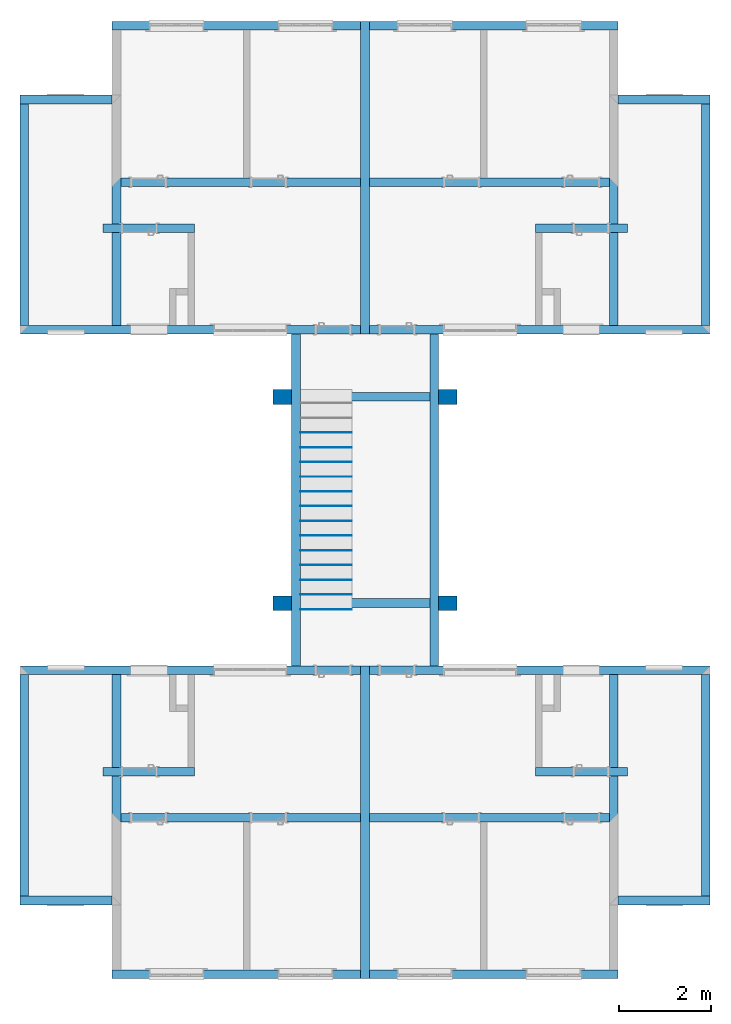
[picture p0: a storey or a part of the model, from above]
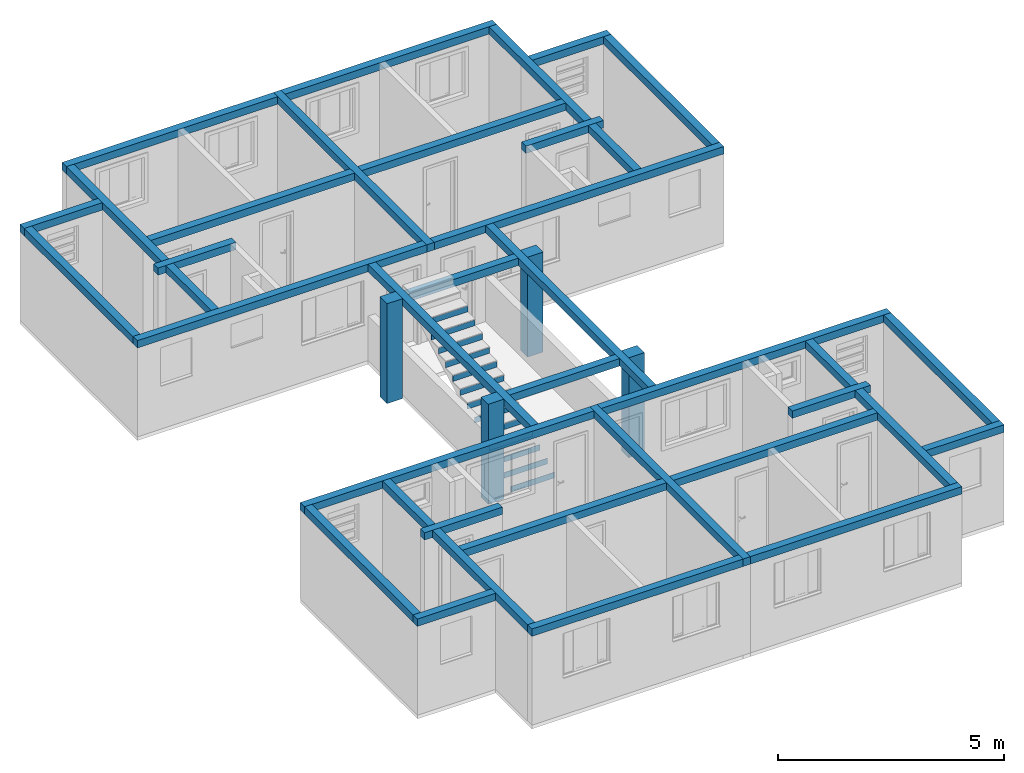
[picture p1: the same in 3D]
Properties of the parts of a building model (IFC2X3)

# File
Description: ViewDefinition [CoordinationView_V2.0, QuantityTakeOffAddOnView], Option [Elements to export: All elements on Current Story], Option [Partial Structure Display: Entire Model], Option [IFC Domain: All], Option [Structural Function: All Elements], Option [Convert Grid elements: On], Option [Convert IFC Annotations and Archicad 2D elements: Off], Option [Convert 2D symbols of Doors and Windows: Off], Option [Export geometries that Participates in Collision Detection only: Off], Option [Split complex elements: Off], Option [Material Preservation: Explode where necessary], Option [Elements in Solid Element Operations: Extruded/revolved], Option [Elements with junctions: Extruded/revolved without junctions], Option [IFC Model position: Survey Point and Project Origin], Option [Curtain Wall export mode: Container Element], Option [Railing export mode: Single Element], Option [Stair export mode: Container Element], Option [Properties To Export: All properties], Option [Space containment: Off], Option [Geometry to type objects: Off], Option [Element Properties: Visible Only], Option [Building Material Properties: Off], Option [Element Parameters: Off], Option [Component Parameters: All], Option [IFC Base Quantities: On], Option [Door Window Parameters: On], Option [IFC Space boundaries: Off], Option [Archicad Zone Categories as IFC Space classification data: Off], Option [Element Classifications: On]
File name: C:\Users\jplen\Downloads\Modelagem - Pavimento tipo V052H-01.ifc
Time: 2024-05-23T11:47:46
Author: Architect
Organization: Building Designer Office
Written by: DDS_IFC v3.0
Made in: IFC file generated by Graphisoft Archicad 27.0.0 BRA FULL Windows version (IFC add-on version: 3001 BRA FULL).
Authorization: The authorising person

# IfcSite, Local
RefLatitude: -23, -32, 0, 0; RefLongitude: -46, -38, 0, 0; RefElevation: 0 mm
BaseQuantities - GrossPerimeter: 0 mm; GrossArea: 0 m2

# IfcBuilding, Construção
BaseQuantities - GrossFloorArea: 217.987 m2

# IfcBuildingStorey, Pavimento Tipo
In: Construção
Elevation: 0 mm
BaseQuantities - NetHeight: 2600 mm; GrossHeight: 2600 mm; Height: 2600 mm; GrossFloorArea: 217.987 m2

# IfcSpace: Circulação (2)
In: Pavimento Tipo
Type - ElementType: EXTERNAL; PredefinedType: USERDEFINED
InteriorOrExteriorSpace: INTERNAL
AC_Pset_RenovationAndPhasing - Renovation Status: Existing
Pset_SpaceCommon - Category: Circulação
BaseQuantities - Height: 2600 mm; FinishCeilingHeight: 2600 mm; FinishFloorHeight: 0 mm; ClearHeight: 2600 mm
Name | LongName | Classification | GrossFloorArea (m2) = NetFloorArea (m2) = SpaceNetFloorAreaBOMA (m2) = SpaceUsableFloorAreaBOMA (m2) = GrossCeilingArea (m2) = NetCeilingArea (m2) | GrossWallArea (m2) | NetWallArea (m2) | GrossPerimeter (mm) = NetPerimeter (mm) | GrossVolume (m3) = NetVolume (m3)
10 | Circulação Horizontal Externa | Espaço Externo (Classificação Archicad); 4A 16 04 04 Saguão (NBR 15965-6 4A) | 14.8841 | 25.032 | 18.312 | 22280 | 38.6987
09 | Caixa de escada | Espaço Externo (Classificação Archicad); 4A 16 01 04 Escada (NBR 15965-6 4A) | 5.376 | 5.76 | 5.76 | 11840 | 13.9776

# IfcSpace: Circulação (4)
In: Pavimento Tipo
Type - ElementType: INTERNAL; PredefinedType: USERDEFINED
LongName: Circulação; InteriorOrExteriorSpace: INTERNAL; Classification: Espaço Residencial (Classificação Archicad); 4A 19 04 10 Circulação (NBR 15965-6 4A)
Pset_SpaceCommon - Category: Circulação
AC_Pset_RenovationAndPhasing - Renovation Status: Existing
BaseQuantities - Height: 2600 mm; FinishCeilingHeight: 2600 mm; FinishFloorHeight: 0 mm; ClearHeight: 2600 mm; GrossFloorArea: 1.4499 m2; NetFloorArea: 1.4499 m2; SpaceNetFloorAreaBOMA: 1.4499 m2; SpaceUsableFloorAreaBOMA: 1.4499 m2; GrossCeilingArea: 1.4499 m2; NetCeilingArea: 1.4499 m2; GrossWallArea: 8.592 m2; NetWallArea: 5.232 m2; GrossPerimeter: 5200 mm; NetPerimeter: 5200 mm; GrossVolume: 3.76974 m3; NetVolume: 3.76974 m3
Name
Apartamento 1 - 06
Apartamento 2 - 06
Apartamento 3 - 06
Apartamento 4 - 06

# IfcSpace: Área privativa (20)
In: Pavimento Tipo
Type - ElementType: INTERNAL; PredefinedType: USERDEFINED
InteriorOrExteriorSpace: INTERNAL
AC_Pset_RenovationAndPhasing - Renovation Status: Existing
BaseQuantities - Height: 2600 mm; FinishCeilingHeight: 2600 mm; FinishFloorHeight: 0 mm; ClearHeight: 2600 mm
Pset_SpaceCommon - Category: Área privativa
Name | LongName | Classification | GrossFloorArea (m2) = NetFloorArea (m2) = SpaceNetFloorAreaBOMA (m2) = SpaceUsableFloorAreaBOMA (m2) = GrossCeilingArea (m2) = NetCeilingArea (m2) | GrossWallArea (m2) | NetWallArea (m2) | GrossPerimeter (mm) = NetPerimeter (mm) | GrossVolume (m3) = NetVolume (m3)
Apartamento 1 - 07 | Cozinha | 4A 19 01 25 Cozinha (NBR 15965-6 4A); Espaço Residencial (Classificação Archicad) | 8.6681 | 30.792 | 29.192 | 13640 | 22.5371
Apartamento 1 - 01 | Quarto 01 | Espaço Residencial (Classificação Archicad); 4A 19 01 01 Dormitório (NBR 15965-6 4A) | 7.7361 | 27.618 | 24.498 | 11240 | 20.1139
Apartamento 1 - 04 | Sala de estar | Espaço Residencial (Classificação Archicad); 4A 19 01 07 Sala de Estar (NBR 15965-6 4A) | 10.8661 | 30.234 | 24.954 | 13240 | 28.2519
Apartamento 1 - 03 | Banheiro | Espaço Residencial (Classificação Archicad); 4A 19 04 07 Banheiro residencial (NBR 15965-6 4A) | 2.6146 | 17.138 | 14.978 | 6940 | 6.79796
Apartamento 1 - 02 | Quarto 02 | Espaço Residencial (Classificação Archicad); 4A 19 01 01 Dormitório (NBR 15965-6 4A) | 8.5386 | 28.818 | 25.698 | 11740 | 22.2004
Apartamento 2 - 07 | Cozinha | 4A 19 01 25 Cozinha (NBR 15965-6 4A); Espaço Residencial (Classificação Archicad) | 8.6681 | 30.792 | 29.192 | 13640 | 22.5371
Apartamento 2 - 01 | Quarto 01 | Espaço Residencial (Classificação Archicad); 4A 19 01 01 Dormitório (NBR 15965-6 4A) | 7.7361 | 27.618 | 24.498 | 11240 | 20.1139
Apartamento 2 - 03 | Banheiro | Espaço Residencial (Classificação Archicad); 4A 19 04 07 Banheiro residencial (NBR 15965-6 4A) | 2.6146 | 17.138 | 14.978 | 6940 | 6.79796
Apartamento 2 - 04 | Sala de estar | Espaço Residencial (Classificação Archicad); 4A 19 01 07 Sala de Estar (NBR 15965-6 4A) | 10.8661 | 30.234 | 24.954 | 13240 | 28.2519
Apartamento 2 - 02 | Quarto 02 | Espaço Residencial (Classificação Archicad); 4A 19 01 01 Dormitório (NBR 15965-6 4A) | 8.5386 | 28.818 | 25.698 | 11740 | 22.2004
Apartamento 3 - 07 | Cozinha | 4A 19 01 25 Cozinha (NBR 15965-6 4A); Espaço Residencial (Classificação Archicad) | 8.6681 | 30.792 | 29.192 | 13640 | 22.5371
Apartamento 3 - 01 | Quarto 01 | Espaço Residencial (Classificação Archicad); 4A 19 01 01 Dormitório (NBR 15965-6 4A) | 7.7361 | 27.618 | 24.498 | 11240 | 20.1139
Apartamento 3 - 04 | Sala de estar | Espaço Residencial (Classificação Archicad); 4A 19 01 07 Sala de Estar (NBR 15965-6 4A) | 10.8661 | 30.234 | 24.954 | 13240 | 28.2519
Apartamento 3 - 03 | Banheiro | Espaço Residencial (Classificação Archicad); 4A 19 04 07 Banheiro residencial (NBR 15965-6 4A) | 2.6146 | 17.138 | 14.978 | 6940 | 6.79796
Apartamento 3 - 02 | Quarto 02 | Espaço Residencial (Classificação Archicad); 4A 19 01 01 Dormitório (NBR 15965-6 4A) | 8.5386 | 28.818 | 25.698 | 11740 | 22.2004
Apartamento 4 - 07 | Cozinha | 4A 19 01 25 Cozinha (NBR 15965-6 4A); Espaço Residencial (Classificação Archicad) | 8.6681 | 30.792 | 29.192 | 13640 | 22.5371
Apartamento 4 - 01 | Quarto 01 | Espaço Residencial (Classificação Archicad); 4A 19 01 01 Dormitório (NBR 15965-6 4A) | 7.7361 | 27.618 | 24.498 | 11240 | 20.1139
Apartamento 4 - 03 | Banheiro | Espaço Residencial (Classificação Archicad); 4A 19 04 07 Banheiro residencial (NBR 15965-6 4A) | 2.6146 | 17.138 | 14.978 | 6940 | 6.79796
Apartamento 4 - 04 | Sala de estar | Espaço Residencial (Classificação Archicad); 4A 19 01 07 Sala de Estar (NBR 15965-6 4A) | 10.8661 | 30.234 | 24.954 | 13240 | 28.2519
Apartamento 4 - 02 | Quarto 02 | Espaço Residencial (Classificação Archicad); 4A 19 01 01 Dormitório (NBR 15965-6 4A) | 8.5386 | 28.818 | 25.698 | 11740 | 22.2004

# IfcSpace: Área técnica (4)
In: Pavimento Tipo
Type - ElementType: INTERNAL; PredefinedType: USERDEFINED
LongName: Shaft do banheiro; InteriorOrExteriorSpace: INTERNAL; Classification: Espaço Residencial (Classificação Archicad); 4A 13 01 13 22 Shaft de Distribuição de Hidráulica (NBR 15965-6 4A)
AC_Pset_RenovationAndPhasing - Renovation Status: Existing
Pset_SpaceCommon - Category: Área técnica
BaseQuantities - Height: 2600 mm; FinishCeilingHeight: 2600 mm; FinishFloorHeight: 0 mm; ClearHeight: 2600 mm; GrossFloorArea: 0.1716 m2; NetFloorArea: 0.1716 m2; SpaceNetFloorAreaBOMA: 0.1716 m2; SpaceUsableFloorAreaBOMA: 0.1716 m2; GrossCeilingArea: 0.1716 m2; NetCeilingArea: 0.1716 m2; GrossWallArea: 4.732 m2; NetWallArea: 4.732 m2; GrossPerimeter: 1840 mm; NetPerimeter: 1840 mm; GrossVolume: 0.44616 m3; NetVolume: 0.44616 m3
Name
Apartamento 1 - 05
Apartamento 2 - 05
Apartamento 3 - 05
Apartamento 4 - 05

# IfcBeam: Concreto - Estrutural 190 x 200 (38)
In: Pavimento Tipo
Type - PredefinedType: BEAM
Classification: 3E 12 06 02 00 Viga (NBR 15965-5 3E); Viga (Classificação Archicad); Material: Concreto - Estrutural
AC_Pset_RenovationAndPhasing - Renovation Status: Existing
Pset_ManufacturerTypeInformation - ProductionYear: DD/MM/YYYY
Pset_BeamCommon - LoadBearing: yes; Reference: Concreto - Estrutural 190 x 200
Component Properties - Concreto - Estrutural, Tipo de Componente: Núcleo
BaseQuantities - Width: 190 mm; Depth: 200 mm; CrossSectionArea: 0.038 m2
Component Quantities - Concreto - Estrutural, Espessura do Componente: 190 mm; Concreto - Estrutural, Altura do Componente Retangular: 200 mm; Concreto - Estrutural, Largura do Componente Retangular: 190 mm; Concreto - Estrutural, Área de Seção Transversal do Componente: 0.038 m2
Name | Description | IsExternal | Concreto - Estrutural, Carbono Incorporado | Concreto - Estrutural, Energia Incorporada (MJ) | NetSurfaceAreaExtrudedSides (m2) = OuterSurfaceArea (m2) | Length (mm) | TotalSurfaceArea (m2) = GrossSurfaceArea (m2) = NetSurfaceArea (m2) | GrossVolume (m3) | NetVolume (m3) = Concreto - Estrutural, Volume Componente (Líquido) (m3) = Concreto - Estrutural, Volume do componente (Bruto) (m3) = Concreto - Estrutural, Volume Componente (Condicional) (m3) | Concreto - Estrutural, Massa (kg) | Concreto - Estrutural, Área de Componente Projetada (Líquida) (m2) = Concreto - Estrutural, Área de Componente Projetada (Bruta) (m2)
Apartamento 1 - V06 | Viga-externa-inloco-concreto_armado-19cm x 20cm | yes | 83.238 (kgCO₂) | 807.156 | 3.7518 | 4810 | 3.8278 | 0.19 | 0.18278 | 420.394 | 0.962
Apartamento 1 - V07 | Viga-interna-inloco-concreto_armado-19cm x 20cm | no | 90.1601 (kgCO₂) | 874.28 | 4.0638 | 5210 | 4.1398 | 0.2052 | 0.19798 | 455.354 | 1.042
Apartamento 1 - V05 | Viga-externa-inloco-concreto_armado-19cm x 20cm | yes | 34.6104 (kgCO₂) | 335.616 | 1.56 | 2000 | 1.636 | 0.076 | 0.076 | 174.8 | 0.4
Apartamento 1 - V04 | Viga-externa-inloco-concreto_armado-19cm x 20cm | yes | 128.058 (kgCO₂) | 1241.78 | 5.772 | 7400 | 5.848 | 0.2812 | 0.2812 | 646.76 | 1.48
Apartamento 1 - V03 | Viga-interna-inloco-concreto_armado-19cm x 20cm | no | 34.4373 (kgCO₂) | 333.938 | 1.5522 | 1990 | 1.6282 | 0.07562 | 0.07562 | 173.926 | 0.398
Apartamento 1 - V01 | Viga-externa-inloco-concreto_armado-19cm x 20cm | yes | 93.4481 (kgCO₂) | 906.163 | 4.212 | 5400 | 4.288 | 0.2052 | 0.2052 | 471.96 | 1.08
Apartamento 1 - V02 | Viga-externa-inloco-concreto_armado-19cm x 20cm | yes | 72.8549 (kgCO₂) | 706.472 | 3.2838 | 4210 | 3.3598 | 0.1672 | 0.15998 | 367.954 | 0.842
Apartamento 1 - V09 | Viga-interna-inloco-concreto_armado-19cm x 20cm | no | 34.7835 (kgCO₂) | 337.294 | 1.5678 | 2010 | 1.6438 | 0.0836 | 0.07638 | 175.674 | 0.402
Apartamentos 1 e 2 - V08 | Viga-interna-inloco-concreto_armado-19cm x 20cm | no | 115.858 (kgCO₂) | 1123.47 | 5.2221 | 6790 | 5.2981 | 0.25441 | 0.25441 | 585.143 | 1.358
Apartamento 2 - V06 | Viga-externa-inloco-concreto_armado-19cm x 20cm | yes | 83.238 (kgCO₂) | 807.156 | 3.7518 | 4810 | 3.8278 | 0.19 | 0.18278 | 420.394 | 0.962
Apartamento 2 - V07 | Viga-interna-inloco-concreto_armado-19cm x 20cm | no | 90.1601 (kgCO₂) | 874.28 | 4.0638 | 5210 | 4.1398 | 0.21242 | 0.19798 | 455.354 | 1.042
Apartamento 2 - V05 | Viga-externa-inloco-concreto_armado-19cm x 20cm | yes | 34.6104 (kgCO₂) | 335.616 | 1.56 | 2000 | 1.636 | 0.076 | 0.076 | 174.8 | 0.4
Apartamento 2 - V04 | Viga-externa-inloco-concreto_armado-19cm x 20cm | yes | 129.702 (kgCO₂) | 1257.72 | 5.8461 | 7590 | 5.9221 | 0.28481 | 0.28481 | 655.063 | 1.518
Apartamento 2 - V02 | Viga-externa-inloco-concreto_armado-19cm x 20cm | yes | 72.8549 (kgCO₂) | 706.472 | 3.2838 | 4210 | 3.3598 | 0.1672 | 0.15998 | 367.954 | 0.842
Apartamento 2 - V03 | Viga-interna-inloco-concreto_armado-19cm x 20cm | no | 34.4373 (kgCO₂) | 333.938 | 1.5522 | 1990 | 1.6282 | 0.07562 | 0.07562 | 173.926 | 0.398
Apartamento 2 - V09 | Viga-interna-inloco-concreto_armado-19cm x 20cm | no | 34.7835 (kgCO₂) | 337.294 | 1.5678 | 2010 | 1.6438 | 0.0836 | 0.07638 | 175.674 | 0.402
Apartamento 2 - V01 | Viga-externa-inloco-concreto_armado-19cm x 20cm | yes | 93.4481 (kgCO₂) | 906.163 | 4.212 | 5400 | 4.288 | 0.21242 | 0.2052 | 471.96 | 1.08
Apartamento 3 - V06 | Viga-externa-inloco-concreto_armado-19cm x 20cm | yes | 83.238 (kgCO₂) | 807.156 | 3.7518 | 4810 | 3.8278 | 0.19 | 0.18278 | 420.394 | 0.962
Apartamento 3 - V07 | Viga-interna-inloco-concreto_armado-19cm x 20cm | no | 90.1601 (kgCO₂) | 874.28 | 4.0638 | 5210 | 4.1398 | 0.2052 | 0.19798 | 455.354 | 1.042
Apartamento 3 - V05 | Viga-externa-inloco-concreto_armado-19cm x 20cm | yes | 34.6104 (kgCO₂) | 335.616 | 1.56 | 2000 | 1.636 | 0.076 | 0.076 | 174.8 | 0.4
Apartamento 3 - V04 | Viga-externa-inloco-concreto_armado-19cm x 20cm | yes | 128.058 (kgCO₂) | 1241.78 | 5.772 | 7400 | 5.848 | 0.2812 | 0.2812 | 646.76 | 1.48
Apartamento 3 - V03 | Viga-interna-inloco-concreto_armado-19cm x 20cm | no | 34.4373 (kgCO₂) | 333.938 | 1.5522 | 1990 | 1.6282 | 0.07562 | 0.07562 | 173.926 | 0.398
Apartamento 3 - V02 | Viga-externa-inloco-concreto_armado-19cm x 20cm | yes | 72.8549 (kgCO₂) | 706.472 | 3.2838 | 4210 | 3.3598 | 0.1672 | 0.15998 | 367.954 | 0.842
Apartamento 3 - V01 | Viga-externa-inloco-concreto_armado-19cm x 20cm | yes | 93.4481 (kgCO₂) | 906.163 | 4.212 | 5400 | 4.288 | 0.2052 | 0.2052 | 471.96 | 1.08
Apartamento 3 - V09 | Viga-interna-inloco-concreto_armado-19cm x 20cm | no | 34.7835 (kgCO₂) | 337.294 | 1.5678 | 2010 | 1.6438 | 0.0836 | 0.07638 | 175.674 | 0.402
Apartamentos 3 e 4 - V08 | Viga-interna-inloco-concreto_armado-19cm x 20cm | no | 115.858 (kgCO₂) | 1123.47 | 5.2221 | 6790 | 5.2981 | 0.25441 | 0.25441 | 585.143 | 1.358
Apartamento 4 - V06 | Viga-externa-inloco-concreto_armado-19cm x 20cm | yes | 83.238 (kgCO₂) | 807.156 | 3.7518 | 4810 | 3.8278 | 0.19 | 0.18278 | 420.394 | 0.962
Apartamento 4 - V07 | Viga-interna-inloco-concreto_armado-19cm x 20cm | no | 90.1601 (kgCO₂) | 874.28 | 4.0638 | 5210 | 4.1398 | 0.21242 | 0.19798 | 455.354 | 1.042
Apartamento 4 - V05 | Viga-externa-inloco-concreto_armado-19cm x 20cm | yes | 34.6104 (kgCO₂) | 335.616 | 1.56 | 2000 | 1.636 | 0.076 | 0.076 | 174.8 | 0.4
Apartamento 4 - V04 | Viga-externa-inloco-concreto_armado-19cm x 20cm | yes | 129.702 (kgCO₂) | 1257.72 | 5.8461 | 7590 | 5.9221 | 0.28481 | 0.28481 | 655.063 | 1.518
Apartamento 4 - V02 | Viga-externa-inloco-concreto_armado-19cm x 20cm | yes | 72.8549 (kgCO₂) | 706.472 | 3.2838 | 4210 | 3.3598 | 0.1672 | 0.15998 | 367.954 | 0.842
Apartamento 4 - V01 | Viga-externa-inloco-concreto_armado-19cm x 20cm | yes | 93.4481 (kgCO₂) | 906.163 | 4.212 | 5400 | 4.288 | 0.21242 | 0.2052 | 471.96 | 1.08
Apartamento 4 - V09 | Viga-interna-inloco-concreto_armado-19cm x 20cm | no | 34.7835 (kgCO₂) | 337.294 | 1.5678 | 2010 | 1.6438 | 0.0836 | 0.07638 | 175.674 | 0.402
Apartamento 4 - V03 | Viga-interna-inloco-concreto_armado-19cm x 20cm | no | 34.4373 (kgCO₂) | 333.938 | 1.5522 | 1990 | 1.6282 | 0.07562 | 0.07562 | 173.926 | 0.398
2 x Núcleo - V03 | Viga-externa-inloco-concreto_armado-19cm x 20cm |  | 124.77 (kgCO₂) | 1209.9 | 5.6238 | 7210 | 5.6998 | 0.28842 | 0.27398 | 630.154 | 1.442
2 x Núcleo - V03 | Viga-externa-inloco-concreto_armado-19cm x 20cm |  | 48.6276 (kgCO₂) | 471.54 | 2.1918 | 2810 | 2.2678 | 0.114 | 0.10678 | 245.594 | 0.562

# IfcColumn: Concreto Armado - Estrutural 400 x 320 (4)
In: Pavimento Tipo
Type - PredefinedType: COLUMN
Classification: Pilar (Classificação Archicad); 3E 12 10 02 02 Pilar (NBR 15965-5 3E); Material: Concreto Armado - Estrutural
Pset_ManufacturerTypeInformation - ProductionYear: DD/MM/YYYY
AC_Pset_RenovationAndPhasing - Renovation Status: Existing
BaseQuantities - Width: 400 mm; Depth: 320 mm; CrossSectionArea: 0.128 m2
Pset_ColumnCommon - LoadBearing: yes; Reference: Concreto Armado - Estrutural 400 x 320
Component Quantities - Concreto Armado - Estrutural, Espessura do Componente: 400 mm; Concreto Armado - Estrutural, Altura do Componente Retangular: 320 mm; Concreto Armado - Estrutural, Largura do Componente Retangular: 400 mm; Concreto Armado - Estrutural, Área de Seção Transversal do Componente: 0.128 m2
Component Properties - Concreto Armado - Estrutural, Tipo de Componente: Núcleo
Name | Length (mm) | OuterSurfaceArea (m2) | TotalSurfaceArea (m2) = GrossSurfaceArea (m2) | GrossVolume (m3) = NetVolume (m3) = Concreto Armado - Estrutural, Volume Componente (Líquido) (m3) = Concreto Armado - Estrutural, Volume do componente (Bruto) (m3) | Concreto Armado - Estrutural, Massa (kg) | Concreto Armado - Estrutural, Carbono Incorporado | Concreto Armado - Estrutural, Energia Incorporada (MJ)
Núcleo - P02 | 2700 | 3.888 | 4.144 | 0.3456 | 829.44 | 200.724 (kgCO₂) | 1932.6
Núcleo - P01 | 2700 | 3.888 | 4.144 | 0.3456 | 829.44 | 200.724 (kgCO₂) | 1932.6
Núcleo - P03 | 2702.18 | 3.89114 | 4.14714 | 0.345879 | 830.11 | 200.887 (kgCO₂) | 1934.16
Núcleo - P04 | 2702.18 | 3.89114 | 4.14714 | 0.345879 | 830.11 | 200.887 (kgCO₂) | 1934.16

# IfcDoor: Porta 27 (8)
In: Pavimento Tipo
Type - OperationType: SINGLE_SWING_LEFT; ParameterTakesPrecedence: no; Sizeable: no
Type - Door Lining Properties - LiningThickness: 50 mm; CasingThickness: 70 mm; CasingDepth: 19 mm
Type - Door Panel Properties - Panel 1 - PanelDepth: 30 mm; PanelOperation: SWINGING; PanelWidth: 1; PanelPosition: MIDDLE
OverallHeight: 2100 mm; OverallWidth: 800 mm; Classification: 3E 20 02 02 04 Porta de girar (NBR 15965-5 3E); Porta (Classificação Archicad)
Pset_DoorCommon - ThermalTransmittance: 0; IsExternal: no
AC_Pset_RenovationAndPhasing - Renovation Status: Existing
BaseQuantities - Height: 2100 mm; Width: 800 mm; Perimeter: 5800 mm; Area: 1.68 m2; Volume: 0.10295 m3; Depth: 190 mm; NetVolume: 0.10295 m3
Component Quantities - Component, Volume Componente (Líquido): 0.10295 m3; Component, Volume do componente (Bruto): 0.10295 m3
Name | Description
Apartamento 1 - P01 | Porta-interna-genérico-madeira-girar- 80cm x 210cm
Apartamento 1 - P02 | Porta-interna-genérico-madeira-girar-80cm x 210cm
Apartamento 2 - P03 | Porta-interna-genérico-madeira-girar-80cm x 210cm
Apartamento 2 - P04 | Porta-interna-genérico-madeira-girar-80cm x 210cm
Apartamento 3 - P01 | Porta-interna-genérico-madeira-girar- 80cm x 210cm
Apartamento 3 - P02 | Porta-interna-genérico-madeira-girar-80cm x 210cm
Apartamento 4 - P04 | Porta-interna-genérico-madeira-girar-80cm x 210cm
Apartamento 4 - P03 | Porta-interna-genérico-madeira-girar-80cm x 210cm

# IfcDoor: Porta 27 (8)
In: Pavimento Tipo
Type - OperationType: SINGLE_SWING_RIGHT; ParameterTakesPrecedence: no; Sizeable: no
Type - Door Lining Properties - LiningThickness: 50 mm; CasingThickness: 70 mm; CasingDepth: 19 mm
Type - Door Panel Properties - Panel 1 - PanelDepth: 30 mm; PanelOperation: SWINGING; PanelWidth: 1; PanelPosition: MIDDLE
OverallHeight: 2100 mm; OverallWidth: 800 mm; Classification: 3E 20 02 02 04 Porta de girar (NBR 15965-5 3E); Porta (Classificação Archicad)
Pset_DoorCommon - ThermalTransmittance: 0; IsExternal: no
AC_Pset_RenovationAndPhasing - Renovation Status: Existing
Component Quantities - Component, Volume Componente (Líquido): 0.10295 m3; Component, Volume do componente (Bruto): 0.10295 m3
BaseQuantities - Height: 2100 mm; Width: 800 mm; Perimeter: 5800 mm; Area: 1.68 m2; Volume: 0.10295 m3; Depth: 190 mm; NetVolume: 0.10295 m3
Name | Description
Apartamento 4 - P02 | Porta-interna-genérico-madeira-girar-80cm x 210cm
Apartamento 1 - P04 | Porta-interna-genérico-madeira-girar-80cm x 210cm
Apartamento 1 - P03 | Porta-interna-genérico-madeira-girar-80cm x 210cm
Apartamento 2 - P01 | Porta-interna-genérico-madeira-girar- 80cm x 210cm
Apartamento 2 - P02 | Porta-interna-genérico-madeira-girar-80cm x 210cm
Apartamento 3 - P03 | Porta-interna-genérico-madeira-girar-80cm x 210cm
Apartamento 3 - P04 | Porta-interna-genérico-madeira-girar-80cm x 210cm
Apartamento 4 - P01 | Porta-interna-genérico-madeira-girar- 80cm x 210cm

# IfcMember: IfcMember (15)
In: Pavimento Tipo
Type - ElementType: Stair Riser; PredefinedType: USERDEFINED
Classification: Espelho de Escada (Classificação Archicad); Material: Madeira
AC_Pset_RenovationAndPhasing - Renovation Status: Existing
Component Properties - Madeira, Carbono Incorporado: 0.270816 (kgCO₂); Madeira, Energia Incorporada: 6.19752 MJ
BaseQuantities - GrossVolume: 0.001736 m3; NetVolume: 0.001736 m3
Component Quantities - Madeira, Massa: 0.5208 kg; Madeira, Volume Componente (Líquido): 0.001736 m3; Madeira, Volume do componente (Bruto): 0.001736 m3

# IfcMember: IfcMember (15)
In: Pavimento Tipo
Type - ElementType: Stair Tread; PredefinedType: USERDEFINED
Classification: Piso de Escada (Classificação Archicad); Material: Madeira
AC_Pset_RenovationAndPhasing - Renovation Status: Existing
Name | GrossVolume (m3) = NetVolume (m3) = Madeira, Volume Componente (Líquido) (m3) = Madeira, Volume do componente (Bruto) (m3) | Madeira, Massa (kg) | Madeira, Carbono Incorporado | Madeira, Energia Incorporada (MJ)
14 x Núcleo - Piso Esc. - 017 | 0.00956207 | 2.86862 | 1.49168 (kgCO₂) | 34.1366
Núcleo - Piso Esc. - 017 | 0.00886207 | 2.65862 | 1.38248 (kgCO₂) | 31.6376

# IfcOpeningElement (40)
In: Pavimento Tipo
BaseQuantities - Depth: 190 mm
Name | Height (mm) | Width (mm) | Area (m2) | Volume (m3)
Apartamento 4 - P02 | 2100 | 800 | 1.68 | 0.10295
Apartamento 1 - J04 | 1000 | 800 | 0.8 | 0.0194095
Apartamento 1 - J06 | 1200 | 1200 | 1.44 | 0.049487
Apartamento 1 - J05 | 1200 | 1200 | 1.44 | 0.049487
Apartamento 1 - J01 | 1200 | 1600 | 1.92 | 0.0569999
Apartamento 1 - J02 | 600 | 800 | 0.48 | 0.0253701
Apartamento 1 - J03 | 1000 | 800 | 0.8 | 0.0194095
Apartamento 1 - P01 | 2100 | 800 | 1.68 | 0.10295
Apartamento 1 - P03 | 2100 | 800 | 1.68 | 0.10295
Apartamento 1 - P04 | 2100 | 800 | 1.68 | 0.10295
Apartamento 2 - J04 | 1000 | 800 | 0.8 | 0.0194095
Apartamento 2 - J06 | 1200 | 1200 | 1.44 | 0.049487
Apartamento 2 - J05 | 1200 | 1200 | 1.44 | 0.049487
Apartamento 2 - J01 | 1200 | 1600 | 1.92 | 0.0569999
Apartamento 2 - J02 | 600 | 800 | 0.48 | 0.0253701
Apartamento 2 - J03 | 1000 | 800 | 0.8 | 0.0194095
Apartamento 1 - P02 | 2100 | 800 | 1.68 | 0.10295
Apartamento 2 - P01 | 2100 | 800 | 1.68 | 0.10295
Apartamento 2 - P03 | 2100 | 800 | 1.68 | 0.10295
Apartamento 2 - P04 | 2100 | 800 | 1.68 | 0.10295
Apartamento 2 - P02 | 2100 | 800 | 1.68 | 0.10295
Apartamento 3 - J04 | 1000 | 800 | 0.8 | 0.0194095
Apartamento 3 - J06 | 1200 | 1200 | 1.44 | 0.049487
Apartamento 3 - J05 | 1200 | 1200 | 1.44 | 0.049487
Apartamento 3 - J01 | 1200 | 1600 | 1.92 | 0.0569999
Apartamento 3 - J02 | 600 | 800 | 0.48 | 0.0253701
Apartamento 3 - J03 | 1000 | 800 | 0.8 | 0.0194095
Apartamento 3 - P01 | 2100 | 800 | 1.68 | 0.10295
Apartamento 3 - P03 | 2100 | 800 | 1.68 | 0.10295
Apartamento 3 - P04 | 2100 | 800 | 1.68 | 0.10295
Apartamento 3 - P02 | 2100 | 800 | 1.68 | 0.10295
Apartamento 4 - J04 | 1000 | 800 | 0.8 | 0.0194095
Apartamento 4 - J06 | 1200 | 1200 | 1.44 | 0.049487
Apartamento 4 - J05 | 1200 | 1200 | 1.44 | 0.049487
Apartamento 4 - J01 | 1200 | 1600 | 1.92 | 0.0569999
Apartamento 4 - J03 | 1000 | 800 | 0.8 | 0.0194095
Apartamento 4 - P01 | 2100 | 800 | 1.68 | 0.10295
Apartamento 4 - J02 | 600 | 800 | 0.48 | 0.0253701
Apartamento 4 - P03 | 2100 | 800 | 1.68 | 0.10295
Apartamento 4 - P04 | 2100 | 800 | 1.68 | 0.10295

# IfcSlab: Concreto 100 (7)
In: Pavimento Tipo
Description: Laje-interna-inloco-concreto_armado-10cm; Classification: Laje (Classificação Archicad); 3E 12 06 08 Laje (NBR 15965-5 3E); Material: Concreto 100 mm
Component Quantities - Concreto, Espessura do Componente: 100 mm
Pset_SlabCommon - LoadBearing: yes
Component Properties - Concreto, Tipo de Componente: Nenhum
AC_Pset_RenovationAndPhasing - Renovation Status: Existing
Pset_ManufacturerTypeInformation - ProductionYear: DD/MM/YYYY
BaseQuantities - Width: 100 mm
Name | Concreto, Massa (kg) | Concreto, Área de Componente Projetada (Líquida) (m2) = Concreto, Área de Componente Projetada (Condicional) (m2) = NetArea (m2) | Concreto, Área de Componente Projetada (Bruta) (m2) = GrossArea (m2) | Concreto, Volume Componente (Líquido) (m3) = NetVolume (m3) | Concreto, Volume do componente (Bruto) (m3) = Concreto, Volume Componente (Condicional) (m3) = GrossVolume (m3) | IsExternal | Concreto, Carbono Incorporado | Concreto, Energia Incorporada (MJ) | Perimeter (mm)
Apartamento 1 - L05 | 8464.96 | 47.0276 | 47.0276 | 4.70276 | 4.70276 | no | 905.751 (kgCO₂) | 6264.07 | 28372.9
Apartamentos 1 e 2 - L03 | 232.218 | 1.2901 | 1.2901 | 0.12901 | 0.12901 | no | 24.8473 (kgCO₂) | 171.841 | 13960
Apartamento 2 - L05 | 8464.96 | 47.0276 | 47.0276 | 4.70276 | 4.70276 | no | 905.751 (kgCO₂) | 6264.07 | 28372.9
Apartamento 3 - L05 | 8464.96 | 47.0276 | 47.0276 | 4.70276 | 4.70276 | no | 905.751 (kgCO₂) | 6264.07 | 28372.9
Apartamento 4 - L05 | 8464.96 | 47.0276 | 47.0276 | 4.70276 | 4.70276 | no | 905.751 (kgCO₂) | 6264.07 | 28372.9
Apartamentos 3 e 4 - L03 | 232.218 | 1.2901 | 1.2901 | 0.12901 | 0.12901 | no | 24.8473 (kgCO₂) | 171.841 | 13960
Núcleo - L05 | 3412.21 | 18.9567 | 22.9999 | 1.89567 | 2.29999 |  | 365.106 (kgCO₂) | 2525.03 | 20800

# IfcStair, Núcleo - Escada - 001
In: Pavimento Tipo
Classification: Escada (Classificação Archicad); 3E 08 06 04 Escada (NBR 15965-5 3E)
Pset_StairCommon - NumberOfRiser: 15; NumberOfTreads: 15; RiserHeight: 180 mm; RequiredHeadroom: 2200 mm
BaseQuantities - Length: 4800 mm; Height: 2700 mm; GrossVolume: 1.24656 m3; NetVolume: 1.24656 m3
AC_Pset_RenovationAndPhasing - Renovation Status: Existing

# IfcStairFlight: IfcStairFlight, Núcleo - Lance - 002
In: Pavimento Tipo
Classification: Lance de Escada (Classificação Archicad); Material: Concreto - Estrutural
Component Properties - Concreto - Estrutural, Carbono Incorporado: 490.826 (kgCO₂); Concreto - Estrutural, Energia Incorporada: 4759.53 MJ
AC_Pset_RenovationAndPhasing - Renovation Status: Existing
Component Quantities - Concreto - Estrutural, Massa: 2478.92 kg; Concreto - Estrutural, Volume Componente (Líquido): 1.07779 m3; Concreto - Estrutural, Volume do componente (Bruto): 1.07779 m3

# IfcWallStandardCase: Concreto - Estrutural 190 (40)
In: Pavimento Tipo
Classification: Parede (Classificação Archicad); 3E 14 02 00 Parede (NBR 15965-5 3E); Material: Concreto - Estrutural 190 mm
Pset_WallCommon - AcousticRating: 0,00
AC_Pset_RenovationAndPhasing - Renovation Status: Existing
Component Properties - Concreto - Estrutural, Tipo de Componente: Nenhum
BaseQuantities - Width: 190 mm
Component Quantities - Concreto - Estrutural, Espessura do Componente: 190 mm; Concreto - Estrutural, Largura do Componente Retangular: 190 mm
Name | Description | IsExternal | LoadBearing | Concreto - Estrutural, Carbono Incorporado | Concreto - Estrutural, Energia Incorporada (MJ) | Length (mm) | Height (mm) | GrossFootprintArea (m2) = NetFootprintArea (m2) | GrossSideArea (m2) = Concreto - Estrutural, Área de Componente Projetada (Bruta) (m2) = Concreto - Estrutural, Área de Componente Projetada (Condicional) (m2) | NetSideArea (m2) | GrossVolume (m3) = Concreto - Estrutural, Volume do componente (Bruto) (m3) = Concreto - Estrutural, Volume Componente (Condicional) (m3) | NetVolume (m3) = Concreto - Estrutural, Volume Componente (Líquido) (m3) | Concreto - Estrutural, Massa (kg) | Concreto - Estrutural, Área de Componente Projetada (Líquida) (m2) | Concreto - Estrutural, Altura do Componente Retangular (mm) | Concreto - Estrutural, Área de Seção Transversal do Componente (m2)
Apartamento 4 - Parede-092 | Parede-interna-inloco-bloco_concreto-estrutural-19cm | no | yes | 267.884 (kgCO₂) | 2597.67 | 1990 | 2400 | 0.2261 | 4.776 | 3.096 | 0.90744 | 0.58824 | 1352.95 | 3.096 | 2600 | 0.494
Apartamento 4 - Parede-091 | Parede-interna-inloco-bloco_concreto-estrutural-19cm | no | yes | 417.401 (kgCO₂) | 4047.53 | 2010 | 2400 | 0.3819 | 4.824 | 4.824 | 0.91656 | 0.91656 | 2108.09 | 4.824 | 2600 | 0.494
Apartamento 1 - Parede-087 | Parede-externa-inloco-bloco_concreto-estrutural-19cm | yes | yes | 345.175 (kgCO₂) | 3347.15 | 2000 | 2400 | 0.38 | 4.8 | 3.988 | 0.912 | 0.75796 | 1743.31 | 4 | 2600 | 0.494
Apartamento 1 - Parede-083 | Parede-interna-inloco-bloco_concreto-estrutural-19cm | no | yes | 413.248 (kgCO₂) | 4007.26 | 1800 | 2400 | 0.3781 | 4.776 | 4.776 | 0.90744 | 0.90744 | 2087.11 | 4.776 | 2600 | 0.494
Apartamento 1 - Parede-005 | Parede-externa-inloco-bloco_concreto-estrutural-19cm | yes | yes | 292.804 (kgCO₂) | 2839.31 | 1410 | 2400 | 0.2679 | 3.384 | 3.384 | 0.64296 | 0.64296 | 1478.81 | 3.384 | 2600 | 0.494
Apartamento 1 - Parede-004 | Parede-externa-inloco-bloco_concreto-estrutural-19cm | yes | yes | 911.638 (kgCO₂) | 8840.13 | 5495 | 2400 | 1.0621 | 13.416 | 10.536 | 2.54904 | 2.00184 | 4604.23 | 10.536 | 2600 | 0.494
Apartamento 1 - Parede-088 | Parede-externa-inloco-bloco_concreto-estrutural-19cm | yes | yes | 1038.31 (kgCO₂) | 10068.5 | 5000 | 2400 | 0.95 | 12 | 12 | 2.28 | 2.28 | 5244 | 12 | 2600 | 0.494
Apartamento 1 - Parede-003 | Parede-externa-inloco-bloco_concreto-estrutural-19cm | yes | yes | 1113.14 (kgCO₂) | 10794.1 | 7400 | 2400 | 1.254 | 17.76 | 12.856 | 3.3744 | 2.44432 | 5621.94 | 12.88 | 2600 | 0.494
Apartamento 1 - Parede-084 | Parede-interna-inloco-bloco_concreto-estrutural-19cm | no | yes | 791.194 (kgCO₂) | 7672.18 | 5305 | 2400 | 0.6859 | 12.504 | 9.144 | 2.37576 | 1.73736 | 3995.93 | 9.144 | 2600 | 0.494
Apartamento 1 - Parede-092 | Parede-interna-inloco-bloco_concreto-estrutural-19cm | no | yes | 267.884 (kgCO₂) | 2597.67 | 1990 | 2400 | 0.2261 | 4.776 | 3.096 | 0.90744 | 0.58824 | 1352.95 | 3.096 | 2600 | 0.494
Apartamento 1 - Parede-091 | Parede-interna-inloco-bloco_concreto-estrutural-19cm | no | yes | 417.401 (kgCO₂) | 4047.53 | 2010 | 2400 | 0.3819 | 4.824 | 4.824 | 0.91656 | 0.91656 | 2108.09 | 4.824 | 2600 | 0.494
Apartamentos 1 e 2 - Parede-002 | Parede-interna-inloco-bloco_concreto-estrutural-19cm | no | yes | 1331.12 (kgCO₂) | 12907.8 | 6600 | 2400 | 1.2179 | 15.384 | 15.384 | 2.92296 | 2.92296 | 6722.81 | 15.384 | 2600 | 0.494
Apartamento 2 - Parede-087 | Parede-externa-inloco-bloco_concreto-estrutural-19cm | yes | yes | 345.175 (kgCO₂) | 3347.15 | 2000 | 2400 | 0.38 | 4.8 | 3.988 | 0.912 | 0.75796 | 1743.31 | 4 | 2600 | 0.494
Apartamento 2 - Parede-083 | Parede-interna-inloco-bloco_concreto-estrutural-19cm | no | yes | 413.248 (kgCO₂) | 4007.26 | 1800 | 2400 | 0.3781 | 4.776 | 4.776 | 0.90744 | 0.90744 | 2087.11 | 4.776 | 2600 | 0.494
Apartamento 2 - Parede-005 | Parede-externa-inloco-bloco_concreto-estrutural-19cm | yes | yes | 292.804 (kgCO₂) | 2839.31 | 1410 | 2400 | 0.2679 | 3.384 | 3.384 | 0.64296 | 0.64296 | 1478.81 | 3.384 | 2600 | 0.494
Apartamento 2 - Parede-004 | Parede-externa-inloco-bloco_concreto-estrutural-19cm | yes | yes | 872.182 (kgCO₂) | 8457.52 | 5400 | 2400 | 1.026 | 12.96 | 10.08 | 2.4624 | 1.9152 | 4404.96 | 10.08 | 2600 | 0.494
Apartamento 2 - Parede-088 | Parede-externa-inloco-bloco_concreto-estrutural-19cm | yes | yes | 1038.31 (kgCO₂) | 10068.5 | 5000 | 2400 | 0.95 | 12 | 12 | 2.28 | 2.28 | 5244 | 12 | 2600 | 0.494
Apartamento 2 - Parede-003 | Parede-externa-inloco-bloco_concreto-estrutural-19cm | yes | yes | 1073.69 (kgCO₂) | 10411.5 | 7305 | 2400 | 1.2179 | 17.304 | 12.4 | 3.28776 | 2.35768 | 5422.66 | 12.424 | 2600 | 0.494
Apartamento 2 - Parede-084 | Parede-interna-inloco-bloco_concreto-estrutural-19cm | no | yes | 791.194 (kgCO₂) | 7672.18 | 5305 | 2400 | 0.6859 | 12.504 | 9.144 | 2.37576 | 1.73736 | 3995.93 | 9.144 | 2600 | 0.494
Apartamento 2 - Parede-092 | Parede-interna-inloco-bloco_concreto-estrutural-19cm | no | yes | 267.884 (kgCO₂) | 2597.67 | 1990 | 2400 | 0.2261 | 4.776 | 3.096 | 0.90744 | 0.58824 | 1352.95 | 3.096 | 2600 | 0.494
Apartamento 2 - Parede-091 | Parede-interna-inloco-bloco_concreto-estrutural-19cm | no | yes | 417.401 (kgCO₂) | 4047.53 | 2010 | 2400 | 0.3819 | 4.824 | 4.824 | 0.91656 | 0.91656 | 2108.09 | 4.824 | 2600 | 0.494
Apartamento 3 - Parede-087 | Parede-externa-inloco-bloco_concreto-estrutural-19cm | yes | yes | 345.175 (kgCO₂) | 3347.15 | 2000 | 2400 | 0.38 | 4.8 | 3.988 | 0.912 | 0.75796 | 1743.31 | 4 | 2600 | 0.494
Apartamento 3 - Parede-083 | Parede-interna-inloco-bloco_concreto-estrutural-19cm | no | yes | 413.248 (kgCO₂) | 4007.26 | 1800 | 2400 | 0.3781 | 4.776 | 4.776 | 0.90744 | 0.90744 | 2087.11 | 4.776 | 2600 | 0.494
Apartamento 3 - Parede-005 | Parede-externa-inloco-bloco_concreto-estrutural-19cm | yes | yes | 292.804 (kgCO₂) | 2839.31 | 1410 | 2400 | 0.2679 | 3.384 | 3.384 | 0.64296 | 0.64296 | 1478.81 | 3.384 | 2600 | 0.494
Apartamento 3 - Parede-004 | Parede-externa-inloco-bloco_concreto-estrutural-19cm | yes | yes | 911.638 (kgCO₂) | 8840.13 | 5495 | 2400 | 1.0621 | 13.416 | 10.536 | 2.54904 | 2.00184 | 4604.23 | 10.536 | 2600 | 0.494
Apartamento 3 - Parede-088 | Parede-externa-inloco-bloco_concreto-estrutural-19cm | yes | yes | 1038.31 (kgCO₂) | 10068.5 | 5000 | 2400 | 0.95 | 12 | 12 | 2.28 | 2.28 | 5244 | 12 | 2600 | 0.494
Apartamento 3 - Parede-003 | Parede-externa-inloco-bloco_concreto-estrutural-19cm | yes | yes | 1113.14 (kgCO₂) | 10794.1 | 7400 | 2400 | 1.254 | 17.76 | 12.856 | 3.3744 | 2.44432 | 5621.94 | 12.88 | 2600 | 0.494
Apartamento 3 - Parede-084 | Parede-interna-inloco-bloco_concreto-estrutural-19cm | no | yes | 791.194 (kgCO₂) | 7672.18 | 5305 | 2400 | 0.6859 | 12.504 | 9.144 | 2.37576 | 1.73736 | 3995.93 | 9.144 | 2600 | 0.494
Apartamento 3 - Parede-092 | Parede-interna-inloco-bloco_concreto-estrutural-19cm | no | yes | 267.884 (kgCO₂) | 2597.67 | 1990 | 2400 | 0.2261 | 4.776 | 3.096 | 0.90744 | 0.58824 | 1352.95 | 3.096 | 2600 | 0.494
Apartamento 3 - Parede-091 | Parede-interna-inloco-bloco_concreto-estrutural-19cm | no | yes | 417.401 (kgCO₂) | 4047.53 | 2010 | 2400 | 0.3819 | 4.824 | 4.824 | 0.91656 | 0.91656 | 2108.09 | 4.824 | 2600 | 0.494
Apartamentos 3 e 4 - Parede-002 | Parede-interna-inloco-bloco_concreto-estrutural-19cm | no | yes | 1331.12 (kgCO₂) | 12907.8 | 6600 | 2400 | 1.2179 | 15.384 | 15.384 | 2.92296 | 2.92296 | 6722.81 | 15.384 | 2600 | 0.494
Apartamento 4 - Parede-087 | Parede-externa-inloco-bloco_concreto-estrutural-19cm | yes | yes | 345.175 (kgCO₂) | 3347.15 | 2000 | 2400 | 0.38 | 4.8 | 3.988 | 0.912 | 0.75796 | 1743.31 | 4 | 2600 | 0.494
Apartamento 4 - Parede-083 | Parede-interna-inloco-bloco_concreto-estrutural-19cm | no | yes | 413.248 (kgCO₂) | 4007.26 | 1800 | 2400 | 0.3781 | 4.776 | 4.776 | 0.90744 | 0.90744 | 2087.11 | 4.776 | 2600 | 0.494
Apartamento 4 - Parede-005 | Parede-externa-inloco-bloco_concreto-estrutural-19cm | yes | yes | 292.804 (kgCO₂) | 2839.31 | 1410 | 2400 | 0.2679 | 3.384 | 3.384 | 0.64296 | 0.64296 | 1478.81 | 3.384 | 2600 | 0.494
Apartamento 4 - Parede-004 | Parede-externa-inloco-bloco_concreto-estrutural-19cm | yes | yes | 872.182 (kgCO₂) | 8457.52 | 5400 | 2400 | 1.026 | 12.96 | 10.08 | 2.4624 | 1.9152 | 4404.96 | 10.08 | 2600 | 0.494
Apartamento 4 - Parede-088 | Parede-externa-inloco-bloco_concreto-estrutural-19cm | yes | yes | 1038.31 (kgCO₂) | 10068.5 | 5000 | 2400 | 0.95 | 12 | 12 | 2.28 | 2.28 | 5244 | 12 | 2600 | 0.494
Apartamento 4 - Parede-003 | Parede-externa-inloco-bloco_concreto-estrutural-19cm | yes | yes | 1073.69 (kgCO₂) | 10411.5 | 7305 | 2400 | 1.2179 | 17.304 | 12.4 | 3.28776 | 2.35768 | 5422.66 | 12.424 | 2600 | 0.494
Apartamento 4 - Parede-084 | Parede-interna-inloco-bloco_concreto-estrutural-19cm | no | yes | 791.194 (kgCO₂) | 7672.18 | 5305 | 2400 | 0.6859 | 12.504 | 9.144 | 2.37576 | 1.73736 | 3995.93 | 9.144 | 2600 | 0.494
2 x Núcleo - Parede-003 | Parede-externa-inloco-bloco_concreto-estrutural-19cm |  |  | 748.623 (kgCO₂) | 7259.37 | 7210 | 1200 | 1.3699 | 8.652 | 8.652 | 1.64388 | 1.64388 | 3780.92 | 8.652 | 1200 | 0.228

# IfcWallStandardCase: Concreto 140 (16)
In: Pavimento Tipo
Description: Parede-interna-inloco-bloco_concreto-14cm; Classification: Parede (Classificação Archicad); 3E 14 02 00 Parede (NBR 15965-5 3E); Material: Concreto 140 mm
AC_Pset_RenovationAndPhasing - Renovation Status: Existing
Pset_WallCommon - IsExternal: no; LoadBearing: no
Component Properties - Concreto, Tipo de Componente: Nenhum
BaseQuantities - Height: 2600 mm; Width: 140 mm
Component Quantities - Concreto, Espessura do Componente: 140 mm; Concreto, Altura do Componente Retangular: 2600 mm; Concreto, Largura do Componente Retangular: 140 mm; Concreto, Área de Seção Transversal do Componente: 0.364 m2
Name | Concreto, Carbono Incorporado | Concreto, Energia Incorporada (MJ) | Length (mm) | GrossFootprintArea (m2) = NetFootprintArea (m2) | GrossSideArea (m2) = NetSideArea (m2) = Concreto, Área de Componente Projetada (Líquida) (m2) = Concreto, Área de Componente Projetada (Bruta) (m2) = Concreto, Área de Componente Projetada (Condicional) (m2) | GrossVolume (m3) = NetVolume (m3) = Concreto, Volume Componente (Líquido) (m3) = Concreto, Volume do componente (Bruto) (m3) = Concreto, Volume Componente (Condicional) (m3) | Concreto, Massa (kg) | AcousticRating
Apartamento 4 - Parede-085 | 225.042 (kgCO₂) | 1556.36 | 3210 | 0.4494 | 8.346 | 1.16844 | 2103.19
Apartamento 1 - Parede-094 | 140.914 (kgCO₂) | 974.544 | 2010 | 0.2814 | 5.226 | 0.73164 | 1316.95 | 0,00
Apartamento 1 - Parede-097 | 18.2277 (kgCO₂) | 126.06 | 260 | 0.0364 | 0.676 | 0.09464 | 170.352 | 0,00
Apartamento 1 - Parede-096 | 56.0851 (kgCO₂) | 387.878 | 800 | 0.112 | 2.08 | 0.2912 | 524.16 | 0,00
Apartamento 1 - Parede-085 | 225.042 (kgCO₂) | 1556.36 | 3210 | 0.4494 | 8.346 | 1.16844 | 2103.19
Apartamento 2 - Parede-094 | 140.914 (kgCO₂) | 974.544 | 2010 | 0.2814 | 5.226 | 0.73164 | 1316.95 | 0,00
Apartamento 2 - Parede-097 | 18.2277 (kgCO₂) | 126.06 | 260 | 0.0364 | 0.676 | 0.09464 | 170.352 | 0,00
Apartamento 2 - Parede-096 | 56.0851 (kgCO₂) | 387.878 | 800 | 0.112 | 2.08 | 0.2912 | 524.16 | 0,00
Apartamento 2 - Parede-085 | 225.042 (kgCO₂) | 1556.36 | 3210 | 0.4494 | 8.346 | 1.16844 | 2103.19
Apartamento 3 - Parede-094 | 140.914 (kgCO₂) | 974.544 | 2010 | 0.2814 | 5.226 | 0.73164 | 1316.95 | 0,00
Apartamento 3 - Parede-097 | 18.2277 (kgCO₂) | 126.06 | 260 | 0.0364 | 0.676 | 0.09464 | 170.352 | 0,00
Apartamento 3 - Parede-096 | 56.0851 (kgCO₂) | 387.878 | 800 | 0.112 | 2.08 | 0.2912 | 524.16 | 0,00
Apartamento 3 - Parede-085 | 225.042 (kgCO₂) | 1556.36 | 3210 | 0.4494 | 8.346 | 1.16844 | 2103.19
Apartamento 4 - Parede-094 | 140.914 (kgCO₂) | 974.544 | 2010 | 0.2814 | 5.226 | 0.73164 | 1316.95 | 0,00
Apartamento 4 - Parede-097 | 18.2277 (kgCO₂) | 126.06 | 260 | 0.0364 | 0.676 | 0.09464 | 170.352 | 0,00
Apartamento 4 - Parede-096 | 56.0851 (kgCO₂) | 387.878 | 800 | 0.112 | 2.08 | 0.2912 | 524.16 | 0,00

# IfcWindow: Janela 27 (4)
In: Pavimento Tipo
Type - OperationType: SINGLE_PANEL; ParameterTakesPrecedence: no; Sizeable: no
Type - Window Lining Properties - LiningDepth: 50 mm; LiningThickness: 47 mm
Type - Window Panel Properties - Panel 1 - OperationType: TOPHUNG; PanelPosition: MIDDLE; FrameDepth: 20 mm; FrameThickness: 50 mm
Description: Janela-externa-genérico-alumínio-maxim_ar-80cm x 60cm; OverallHeight: 600 mm; OverallWidth: 800 mm; Classification: Janela (Classificação Archicad); 3E 20 04 02 06 Janela basculante (NBR 15965-5 3E)
Pset_WindowCommon - ThermalTransmittance: 0
AC_Pset_RenovationAndPhasing - Renovation Status: Existing
Component Quantities - Component, Volume Componente (Líquido): 0.0253701 m3; Component, Volume do componente (Bruto): 0.0253701 m3
BaseQuantities - GrossArea: 0.48 m2; Height: 600 mm; Width: 800 mm; Perimeter: 2800 mm; Area: 0.48 m2; Volume: 0.0253701 m3; Depth: 190 mm; NetVolume: 0.0253701 m3
Name
Apartamento 1 - J02
Apartamento 2 - J02
Apartamento 3 - J02
Apartamento 4 - J02

# IfcWindow: Janela Multi-Caixilho Vertical 27 (8)
In: Pavimento Tipo
Type - OperationType: USERDEFINED; ParameterTakesPrecedence: no; Sizeable: no
Description: Janela-externa-genérico-alumínio-basculante-80cm x 100cm; OverallHeight: 1000 mm; OverallWidth: 800 mm; Classification: Janela (Classificação Archicad); 3E 20 04 02 06 Janela basculante (NBR 15965-5 3E)
Pset_WindowCommon - ThermalTransmittance: 0
AC_Pset_RenovationAndPhasing - Renovation Status: Existing
BaseQuantities - GrossArea: 0.8 m2; Height: 1000 mm; Width: 800 mm; Perimeter: 3600 mm; Area: 0.8 m2; Volume: 0.0194095 m3; Depth: 190 mm; NetVolume: 0.0194095 m3
Component Quantities - Component, Volume Componente (Líquido): 0.0194095 m3; Component, Volume do componente (Bruto): 0.0194095 m3
Name
Apartamento 1 - J04
Apartamento 1 - J03
Apartamento 2 - J04
Apartamento 2 - J03
Apartamento 3 - J04
Apartamento 3 - J03
Apartamento 4 - J04
Apartamento 4 - J03

# IfcWindow: Janela de Correr 4-Folhas 27 (12)
In: Pavimento Tipo
Type - OperationType: USERDEFINED; ParameterTakesPrecedence: no; Sizeable: no
OverallHeight: 1200 mm; Classification: Janela (Classificação Archicad); 3E 20 04 02 02 Janela de correr (NBR 15965-5 3E)
Pset_WindowCommon - ThermalTransmittance: 0
AC_Pset_RenovationAndPhasing - Renovation Status: Existing
BaseQuantities - Height: 1200 mm; Depth: 190 mm
Name | Description | OverallWidth (mm) = Width (mm) | GrossArea (m2) = Area (m2) | Perimeter (mm) | Volume (m3) = NetVolume (m3) = Component, Volume Componente (Líquido) (m3) = Component, Volume do componente (Bruto) (m3)
Apartamento 1 - J06 | Janela-externa-genérico-alumínio-correr-120cm x 120cm | 1200 | 1.44 | 4800 | 0.049487
Apartamento 1 - J05 | Janela-externa-genérico-alumínio-correr-120cm x 120cm | 1200 | 1.44 | 4800 | 0.049487
Apartamento 1 - J01 | Janela-externa-genérico-alumínio-correr-160cm x 120cm | 1600 | 1.92 | 5600 | 0.0569999
Apartamento 2 - J05 | Janela-externa-genérico-alumínio-correr-120cm x 120cm | 1200 | 1.44 | 4800 | 0.049487
Apartamento 2 - J06 | Janela-externa-genérico-alumínio-correr-120cm x 120cm | 1200 | 1.44 | 4800 | 0.049487
Apartamento 2 - J01 | Janela-externa-genérico-alumínio-correr-160cm x 120cm | 1600 | 1.92 | 5600 | 0.0569999
Apartamento 3 - J06 | Janela-externa-genérico-alumínio-correr-120cm x 120cm | 1200 | 1.44 | 4800 | 0.049487
Apartamento 3 - J05 | Janela-externa-genérico-alumínio-correr-120cm x 120cm | 1200 | 1.44 | 4800 | 0.049487
Apartamento 3 - J01 | Janela-externa-genérico-alumínio-correr-160cm x 120cm | 1600 | 1.92 | 5600 | 0.0569999
Apartamento 4 - J05 | Janela-externa-genérico-alumínio-correr-120cm x 120cm | 1200 | 1.44 | 4800 | 0.049487
Apartamento 4 - J06 | Janela-externa-genérico-alumínio-correr-120cm x 120cm | 1200 | 1.44 | 4800 | 0.049487
Apartamento 4 - J01 | Janela-externa-genérico-alumínio-correr-160cm x 120cm | 1600 | 1.92 | 5600 | 0.0569999
